NAMESCASESENSITIVE ON ;

UNITS
DATABASE MICRONS 1000 ;
END UNITS

LAYER NWELL
	TYPE MASTERSLICE ;
END NWELL
LAYER PP
	TYPE MASTERSLICE ;
END PP
LAYER NP
	TYPE MASTERSLICE ;
END NP
LAYER OD
	TYPE MASTERSLICE ;
END OD
LAYER POLY
	TYPE MASTERSLICE ;
END POLY
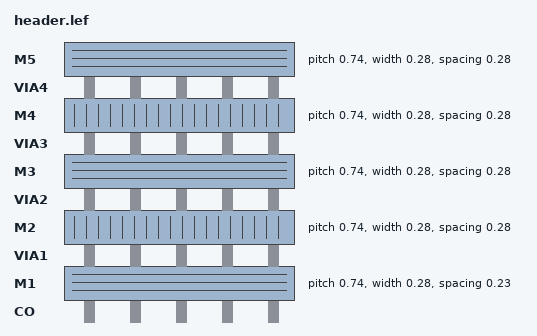
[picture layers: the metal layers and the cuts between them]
LAYER CO
	TYPE CUT ;
END CO
LAYER M1
	TYPE ROUTING ;
	PITCH 0.74 ;
	WIDTH 0.28 ;
	SPACING 0.23 ;
	DIRECTION HORIZONTAL ;
	RESISTANCE RPERSQ 0.11 ;
	CAPACITANCE CPERSQDIST .000389 ;
END M1
LAYER VIA1 
	TYPE CUT ;
END VIA1
LAYER M2
	TYPE ROUTING ;
	PITCH 0.74 ;
	WIDTH 0.28 ;
	SPACING 0.28 ;
	DIRECTION VERTICAL ;
	RESISTANCE RPERSQ 0.11 ;
	CAPACITANCE CPERSQDIST .000353 ;
END M2
LAYER VIA2
	TYPE CUT ;
END VIA2
LAYER M3
	TYPE ROUTING ;
	PITCH 0.74 ;
	WIDTH 0.28 ;
	SPACING 0.28 ;
	DIRECTION HORIZONTAL ;
	RESISTANCE RPERSQ 0.11 ;
	CAPACITANCE CPERSQDIST .000320 ;
END M3
LAYER VIA3
	TYPE CUT ;
END VIA3
LAYER M4
	TYPE ROUTING ;
	PITCH 0.74 ;
	WIDTH 0.28 ;
	SPACING 0.28 ;
	DIRECTION VERTICAL ;
	RESISTANCE RPERSQ 0.11 ;
	CAPACITANCE CPERSQDIST .000296 ;
END M4
LAYER VIA4
	TYPE CUT ;
END VIA4
LAYER M5
	TYPE ROUTING ;
	PITCH 0.74 ;
	WIDTH 0.28 ;
	SPACING 0.28 ;
	DIRECTION HORIZONTAL ;
	RESISTANCE RPERSQ 0.06 ;
	CAPACITANCE CPERSQDIST .000296 ;
END M5
VIA VIA12 DEFAULT
	RESISTANCE 1.21 ;
	LAYER M1 ; RECT -0.19 -0.19 0.19 0.19 ;
	LAYER VIA1 ; RECT -0.13 -0.13 0.13 0.13 ;
	LAYER M2 ; RECT -0.23 -0.23 0.23 0.23 ;
END VIA12
VIA VIA23 DEFAULT
	RESISTANCE 1.07 ;
	LAYER M2 ; RECT -0.23 -0.23 0.23 0.23 ;
	LAYER VIA2 ; RECT -0.13 -0.13 0.13 0.13 ;
	LAYER M3 ; RECT -0.23 -0.23 0.23 0.23 ;
END VIA23
VIA VIA34 DEFAULT
	RESISTANCE 1.19 ;
	LAYER M3 ; RECT -0.23 -0.23 0.23 0.23 ;
	LAYER VIA3 ; RECT -0.13 -0.13 0.13 0.13 ;
	LAYER M4 ; RECT -0.23 -0.23 0.23 0.23 ;
END VIA34
VIA VIA45 DEFAULT
	RESISTANCE 1.19 ;
	LAYER M4 ; RECT -0.23 -0.23 0.23 0.23 ;
	LAYER VIA4 ; RECT -0.13 -0.13 0.13 0.13 ;
	LAYER M5 ; RECT -0.23 -0.23 0.23 0.23 ;
END VIA45
VIARULE TURN1 GENERATE
	LAYER M1 ; DIRECTION HORIZONTAL ;
	LAYER M1 ; DIRECTION VERTICAL ;
END TURN1
VIARULE TURN2 GENERATE
	LAYER M2 ; DIRECTION VERTICAL ;
	LAYER M2 ; DIRECTION HORIZONTAL ;
END TURN2
VIARULE TURN3 GENERATE
	LAYER M3 ; DIRECTION HORIZONTAL ;
	LAYER M3 ; DIRECTION VERTICAL ;
END TURN3
VIARULE TURN4 GENERATE
	LAYER M4 ; DIRECTION VERTICAL ;
	LAYER M4 ; DIRECTION HORIZONTAL ;
END TURN4
VIARULE TURN5 GENERATE
	LAYER M5 ; DIRECTION HORIZONTAL ;
	LAYER M5 ; DIRECTION VERTICAL ;
END TURN5
VIARULE ONEVIA12
	LAYER M1 ; DIRECTION HORIZONTAL ; WIDTH 0.5 TO 0.9 ;
	LAYER M2 ; DIRECTION VERTICAL ; WIDTH 0.6 TO 0.9 ;
	VIA VIA12 ;
END ONEVIA12
VIARULE ONEVIA23
	LAYER M2 ; DIRECTION VERTICAL ; WIDTH 0.6 TO 0.9 ;
	LAYER M3 ; DIRECTION HORIZONTAL ; WIDTH 0.6 TO 0.9 ;
	VIA VIA23 ;
END ONEVIA23
VIARULE ONEVIA34
	LAYER M3 ; DIRECTION HORIZONTAL ; WIDTH 0.6 TO 0.9 ;
	LAYER M4 ; DIRECTION VERTICAL ; WIDTH 0.6 TO 0.9 ;
	VIA VIA34 ;
END ONEVIA34
VIARULE ONEVIA45
	LAYER M4 ; DIRECTION VERTICAL ; WIDTH 0.6 TO 0.9 ;
	LAYER M5 ; DIRECTION HORIZONTAL ; WIDTH 0.6 TO 0.9 ;
	VIA VIA45 ;
END ONEVIA45
VIARULE VIAGEN12 GENERATE
	LAYER M1 ; DIRECTION HORIZONTAL ; OVERHANG 0.06 ; METALOVERHANG 0.06 ;
	LAYER M2 ; DIRECTION VERTICAL ; OVERHANG 0.06 ; METALOVERHANG 0.06 ;
	LAYER VIA1 ; RECT  -0.13 -0.13 0.13 0.13 ; SPACING 0.74 BY 0.74 ;
END VIAGEN12
VIARULE VIAGEN23 GENERATE
	LAYER M2 ; DIRECTION VERTICAL ; OVERHANG 0.06 ; METALOVERHANG 0.06 ;
	LAYER M3 ; DIRECTION HORIZONTAL ; OVERHANG 0.06 ; METALOVERHANG 0.06 ;
	LAYER VIA2 ; RECT  -0.13 -0.13 0.13 0.13 ; SPACING 0.74 BY 0.74 ;
END VIAGEN23
VIARULE VIAGEN34 GENERATE
	LAYER M3 ; DIRECTION HORIZONTAL ; OVERHANG 0.06 ; METALOVERHANG 0.06 ;
	LAYER M4 ; DIRECTION VERTICAL ; OVERHANG 0.06 ; METALOVERHANG 0.06 ;
	LAYER VIA3 ; RECT  -0.13 -0.13 0.13 0.13 ; SPACING 0.74 BY 0.74 ;
END VIAGEN34
VIARULE VIAGEN45 GENERATE
	LAYER M4 ; DIRECTION VERTICAL ; OVERHANG 0.06 ; METALOVERHANG 0.06 ;
	LAYER M5 ; DIRECTION HORIZONTAL ; OVERHANG 0.06 ; METALOVERHANG 0.06 ;
	LAYER VIA4 ; RECT  -0.13 -0.13 0.13 0.13 ; SPACING 0.74 BY 0.74 ;
END VIAGEN45
SPACING
        SAMENET M1 M1 0.23 STACK ;
        SAMENET M2 M2 0.28 STACK ;
        SAMENET M3 M3 0.28 STACK ;
        SAMENET M4 M4 0.28 STACK ;
        SAMENET M5 M5 0.28 ;
	SAMENET VIA1 VIA1 0.26 STACK ;
        SAMENET VIA1 VIA2 0.00 STACK ;
	SAMENET VIA2 VIA2 0.26 STACK ;
        SAMENET VIA2 VIA3 0.00 STACK ;
	SAMENET VIA3 VIA3 0.26 STACK ;
        SAMENET VIA3 VIA4 0.00 STACK ;
	SAMENET VIA4 VIA4 0.26 STACK ;
END SPACING
MINFEATURE 0.005 0.005 ;
SITE CORE1
	SIZE 1.0 BY 7.4 ;
	CLASS CORE ;
	SYMMETRY Y ;
END CORE1
